VERSION 5.7 ;
  NOWIREEXTENSIONATPIN ON ;
  DIVIDERCHAR "/" ;
  BUSBITCHARS "[]" ;
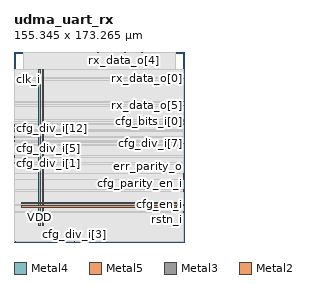
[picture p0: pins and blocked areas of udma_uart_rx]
MACRO udma_uart_rx
  CLASS BLOCK ;
  FOREIGN udma_uart_rx ;
  ORIGIN 0.000 0.000 ;
  SIZE 155.345 BY 173.265 ;
  PIN VDD
    DIRECTION INOUT ;
    USE POWER ;
    PORT
      LAYER Metal4 ;
        RECT 22.240 15.380 23.840 157.100 ;
    END
    PORT
      LAYER Metal5 ;
        RECT 6.720 31.530 148.400 33.130 ;
    END
  END VDD
  PIN VSS
    DIRECTION INOUT ;
    USE GROUND ;
    PORT
      LAYER Metal4 ;
        RECT 25.540 15.380 27.140 157.100 ;
    END
    PORT
      LAYER Metal5 ;
        RECT 6.720 34.830 148.400 36.430 ;
    END
  END VSS
  PIN busy_o
    DIRECTION OUTPUT ;
    USE SIGNAL ;
    ANTENNADIFFAREA 0.897600 ;
    PORT
      LAYER Metal3 ;
        RECT 154.785 47.040 155.345 47.600 ;
    END
  END busy_o
  PIN cfg_bits_i[0]
    DIRECTION INPUT ;
    USE SIGNAL ;
    ANTENNAGATEAREA 0.396000 ;
    PORT
      LAYER Metal3 ;
        RECT 154.785 109.760 155.345 110.320 ;
    END
  END cfg_bits_i[0]
  PIN cfg_bits_i[1]
    DIRECTION INPUT ;
    USE SIGNAL ;
    ANTENNAGATEAREA 0.396000 ;
    PORT
      LAYER Metal3 ;
        RECT 154.785 110.880 155.345 111.440 ;
    END
  END cfg_bits_i[1]
  PIN cfg_div_i[0]
    DIRECTION INPUT ;
    USE SIGNAL ;
    ANTENNAGATEAREA 0.396000 ;
    PORT
      LAYER Metal3 ;
        RECT 0.000 70.560 0.560 71.120 ;
    END
  END cfg_div_i[0]
  PIN cfg_div_i[10]
    DIRECTION INPUT ;
    USE SIGNAL ;
    ANTENNAGATEAREA 0.396000 ;
    PORT
      LAYER Metal3 ;
        RECT 0.000 104.160 0.560 104.720 ;
    END
  END cfg_div_i[10]
  PIN cfg_div_i[11]
    DIRECTION INPUT ;
    USE SIGNAL ;
    ANTENNAGATEAREA 0.396000 ;
    PORT
      LAYER Metal3 ;
        RECT 0.000 91.840 0.560 92.400 ;
    END
  END cfg_div_i[11]
  PIN cfg_div_i[12]
    DIRECTION INPUT ;
    USE SIGNAL ;
    ANTENNAGATEAREA 0.396000 ;
    PORT
      LAYER Metal3 ;
        RECT 0.000 103.040 0.560 103.600 ;
    END
  END cfg_div_i[12]
  PIN cfg_div_i[13]
    DIRECTION INPUT ;
    USE SIGNAL ;
    ANTENNAGATEAREA 0.396000 ;
    PORT
      LAYER Metal3 ;
        RECT 0.000 106.400 0.560 106.960 ;
    END
  END cfg_div_i[13]
  PIN cfg_div_i[14]
    DIRECTION INPUT ;
    USE SIGNAL ;
    ANTENNAGATEAREA 0.396000 ;
    PORT
      LAYER Metal3 ;
        RECT 0.000 100.800 0.560 101.360 ;
    END
  END cfg_div_i[14]
  PIN cfg_div_i[15]
    DIRECTION INPUT ;
    USE SIGNAL ;
    ANTENNAGATEAREA 0.396000 ;
    PORT
      LAYER Metal3 ;
        RECT 0.000 89.600 0.560 90.160 ;
    END
  END cfg_div_i[15]
  PIN cfg_div_i[1]
    DIRECTION INPUT ;
    USE SIGNAL ;
    ANTENNAGATEAREA 0.396000 ;
    PORT
      LAYER Metal3 ;
        RECT 0.000 71.680 0.560 72.240 ;
    END
  END cfg_div_i[1]
  PIN cfg_div_i[2]
    DIRECTION INPUT ;
    USE SIGNAL ;
    ANTENNAGATEAREA 0.396000 ;
    PORT
      LAYER Metal3 ;
        RECT 0.000 95.200 0.560 95.760 ;
    END
  END cfg_div_i[2]
  PIN cfg_div_i[3]
    DIRECTION INPUT ;
    USE SIGNAL ;
    ANTENNAGATEAREA 0.396000 ;
    PORT
      LAYER Metal2 ;
        RECT 54.880 0.000 55.440 0.560 ;
    END
  END cfg_div_i[3]
  PIN cfg_div_i[4]
    DIRECTION INPUT ;
    USE SIGNAL ;
    ANTENNAGATEAREA 0.396000 ;
    PORT
      LAYER Metal3 ;
        RECT 0.000 77.280 0.560 77.840 ;
    END
  END cfg_div_i[4]
  PIN cfg_div_i[5]
    DIRECTION INPUT ;
    USE SIGNAL ;
    ANTENNAGATEAREA 0.396000 ;
    PORT
      LAYER Metal3 ;
        RECT 0.000 78.400 0.560 78.960 ;
    END
  END cfg_div_i[5]
  PIN cfg_div_i[6]
    DIRECTION INPUT ;
    USE SIGNAL ;
    ANTENNAGATEAREA 0.396000 ;
    PORT
      LAYER Metal3 ;
        RECT 0.000 88.480 0.560 89.040 ;
    END
  END cfg_div_i[6]
  PIN cfg_div_i[7]
    DIRECTION INPUT ;
    USE SIGNAL ;
    ANTENNAGATEAREA 0.396000 ;
    PORT
      LAYER Metal3 ;
        RECT 154.785 89.600 155.345 90.160 ;
    END
  END cfg_div_i[7]
  PIN cfg_div_i[8]
    DIRECTION INPUT ;
    USE SIGNAL ;
    ANTENNAGATEAREA 0.396000 ;
    PORT
      LAYER Metal2 ;
        RECT 76.160 172.705 76.720 173.265 ;
    END
  END cfg_div_i[8]
  PIN cfg_div_i[9]
    DIRECTION INPUT ;
    USE SIGNAL ;
    ANTENNAGATEAREA 0.396000 ;
    PORT
      LAYER Metal3 ;
        RECT 0.000 105.280 0.560 105.840 ;
    END
  END cfg_div_i[9]
  PIN cfg_en_i
    DIRECTION INPUT ;
    USE SIGNAL ;
    ANTENNAGATEAREA 0.396000 ;
    PORT
      LAYER Metal3 ;
        RECT 154.785 33.600 155.345 34.160 ;
    END
  END cfg_en_i
  PIN cfg_parity_en_i
    DIRECTION INPUT ;
    USE SIGNAL ;
    ANTENNAGATEAREA 0.396000 ;
    PORT
      LAYER Metal3 ;
        RECT 154.785 45.920 155.345 46.480 ;
    END
  END cfg_parity_en_i
  PIN cfg_stop_bits_i
    DIRECTION INPUT ;
    USE SIGNAL ;
    PORT
      LAYER Metal2 ;
        RECT 1.120 0.000 1.680 0.560 ;
    END
  END cfg_stop_bits_i
  PIN char_event_o
    DIRECTION OUTPUT ;
    USE SIGNAL ;
    ANTENNADIFFAREA 0.897600 ;
    PORT
      LAYER Metal3 ;
        RECT 154.785 57.120 155.345 57.680 ;
    END
  END char_event_o
  PIN clk_i
    DIRECTION INPUT ;
    USE SIGNAL ;
    ANTENNAGATEAREA 4.738000 ;
    PORT
      LAYER Metal3 ;
        RECT 0.000 147.840 0.560 148.400 ;
    END
  END clk_i
  PIN err_overflow_o
    DIRECTION OUTPUT ;
    USE SIGNAL ;
    ANTENNADIFFAREA 0.897600 ;
    PORT
      LAYER Metal3 ;
        RECT 154.785 58.240 155.345 58.800 ;
    END
  END err_overflow_o
  PIN err_parity_o
    DIRECTION OUTPUT ;
    USE SIGNAL ;
    ANTENNADIFFAREA 0.897600 ;
    PORT
      LAYER Metal3 ;
        RECT 154.785 61.600 155.345 62.160 ;
    END
  END err_parity_o
  PIN rstn_i
    DIRECTION INPUT ;
    USE SIGNAL ;
    ANTENNAGATEAREA 0.396000 ;
    PORT
      LAYER Metal3 ;
        RECT 154.785 26.880 155.345 27.440 ;
    END
  END rstn_i
  PIN rx_data_o[0]
    DIRECTION OUTPUT ;
    USE SIGNAL ;
    ANTENNADIFFAREA 0.897600 ;
    PORT
      LAYER Metal3 ;
        RECT 154.785 148.960 155.345 149.520 ;
    END
  END rx_data_o[0]
  PIN rx_data_o[1]
    DIRECTION OUTPUT ;
    USE SIGNAL ;
    ANTENNADIFFAREA 0.897600 ;
    PORT
      LAYER Metal2 ;
        RECT 133.280 172.705 133.840 173.265 ;
    END
  END rx_data_o[1]
  PIN rx_data_o[2]
    DIRECTION OUTPUT ;
    USE SIGNAL ;
    ANTENNADIFFAREA 0.897600 ;
    PORT
      LAYER Metal2 ;
        RECT 116.480 172.705 117.040 173.265 ;
    END
  END rx_data_o[2]
  PIN rx_data_o[3]
    DIRECTION OUTPUT ;
    USE SIGNAL ;
    ANTENNADIFFAREA 0.897600 ;
    PORT
      LAYER Metal2 ;
        RECT 100.800 172.705 101.360 173.265 ;
    END
  END rx_data_o[3]
  PIN rx_data_o[4]
    DIRECTION OUTPUT ;
    USE SIGNAL ;
    ANTENNADIFFAREA 0.897600 ;
    PORT
      LAYER Metal2 ;
        RECT 99.680 172.705 100.240 173.265 ;
    END
  END rx_data_o[4]
  PIN rx_data_o[5]
    DIRECTION OUTPUT ;
    USE SIGNAL ;
    ANTENNADIFFAREA 0.897600 ;
    PORT
      LAYER Metal3 ;
        RECT 154.785 124.320 155.345 124.880 ;
    END
  END rx_data_o[5]
  PIN rx_data_o[6]
    DIRECTION OUTPUT ;
    USE SIGNAL ;
    ANTENNADIFFAREA 0.897600 ;
    PORT
      LAYER Metal3 ;
        RECT 154.785 127.680 155.345 128.240 ;
    END
  END rx_data_o[6]
  PIN rx_data_o[7]
    DIRECTION OUTPUT ;
    USE SIGNAL ;
    ANTENNADIFFAREA 0.897600 ;
    PORT
      LAYER Metal3 ;
        RECT 154.785 107.520 155.345 108.080 ;
    END
  END rx_data_o[7]
  PIN rx_i
    DIRECTION INPUT ;
    USE SIGNAL ;
    ANTENNAGATEAREA 0.396000 ;
    PORT
      LAYER Metal2 ;
        RECT 84.000 0.000 84.560 0.560 ;
    END
  END rx_i
  PIN rx_ready_i
    DIRECTION INPUT ;
    USE SIGNAL ;
    ANTENNAGATEAREA 0.396000 ;
    PORT
      LAYER Metal3 ;
        RECT 154.785 59.360 155.345 59.920 ;
    END
  END rx_ready_i
  PIN rx_valid_o
    DIRECTION OUTPUT ;
    USE SIGNAL ;
    ANTENNADIFFAREA 0.897600 ;
    PORT
      LAYER Metal3 ;
        RECT 154.785 60.480 155.345 61.040 ;
    END
  END rx_valid_o
  OBS
      LAYER Nwell ;
        RECT 6.290 15.250 148.830 157.230 ;
      LAYER Metal1 ;
        RECT 6.720 15.380 148.400 157.100 ;
      LAYER Metal2 ;
        RECT 9.100 172.405 75.860 173.125 ;
        RECT 77.020 172.405 99.380 173.125 ;
        RECT 101.660 172.405 116.180 173.125 ;
        RECT 117.340 172.405 132.980 173.125 ;
        RECT 134.140 172.405 147.140 173.125 ;
        RECT 9.100 0.860 147.140 172.405 ;
        RECT 9.100 0.560 54.580 0.860 ;
        RECT 55.740 0.560 83.700 0.860 ;
        RECT 84.860 0.560 147.140 0.860 ;
      LAYER Metal3 ;
        RECT 0.560 149.820 154.785 156.940 ;
        RECT 0.560 148.700 154.485 149.820 ;
        RECT 0.860 148.660 154.485 148.700 ;
        RECT 0.860 147.540 154.785 148.660 ;
        RECT 0.560 128.540 154.785 147.540 ;
        RECT 0.560 127.380 154.485 128.540 ;
        RECT 0.560 125.180 154.785 127.380 ;
        RECT 0.560 124.020 154.485 125.180 ;
        RECT 0.560 111.740 154.785 124.020 ;
        RECT 0.560 109.460 154.485 111.740 ;
        RECT 0.560 108.380 154.785 109.460 ;
        RECT 0.560 107.260 154.485 108.380 ;
        RECT 0.860 107.220 154.485 107.260 ;
        RECT 0.860 102.740 154.785 107.220 ;
        RECT 0.560 101.660 154.785 102.740 ;
        RECT 0.860 100.500 154.785 101.660 ;
        RECT 0.560 96.060 154.785 100.500 ;
        RECT 0.860 94.900 154.785 96.060 ;
        RECT 0.560 92.700 154.785 94.900 ;
        RECT 0.860 91.540 154.785 92.700 ;
        RECT 0.560 90.460 154.785 91.540 ;
        RECT 0.860 89.300 154.485 90.460 ;
        RECT 0.860 88.180 154.785 89.300 ;
        RECT 0.560 79.260 154.785 88.180 ;
        RECT 0.860 76.980 154.785 79.260 ;
        RECT 0.560 72.540 154.785 76.980 ;
        RECT 0.860 70.260 154.785 72.540 ;
        RECT 0.560 62.460 154.785 70.260 ;
        RECT 0.560 56.820 154.485 62.460 ;
        RECT 0.560 47.900 154.785 56.820 ;
        RECT 0.560 45.620 154.485 47.900 ;
        RECT 0.560 34.460 154.785 45.620 ;
        RECT 0.560 33.300 154.485 34.460 ;
        RECT 0.560 27.740 154.785 33.300 ;
        RECT 0.560 26.580 154.485 27.740 ;
        RECT 0.560 0.700 154.785 26.580 ;
  END
END udma_uart_rx
END LIBRARY

